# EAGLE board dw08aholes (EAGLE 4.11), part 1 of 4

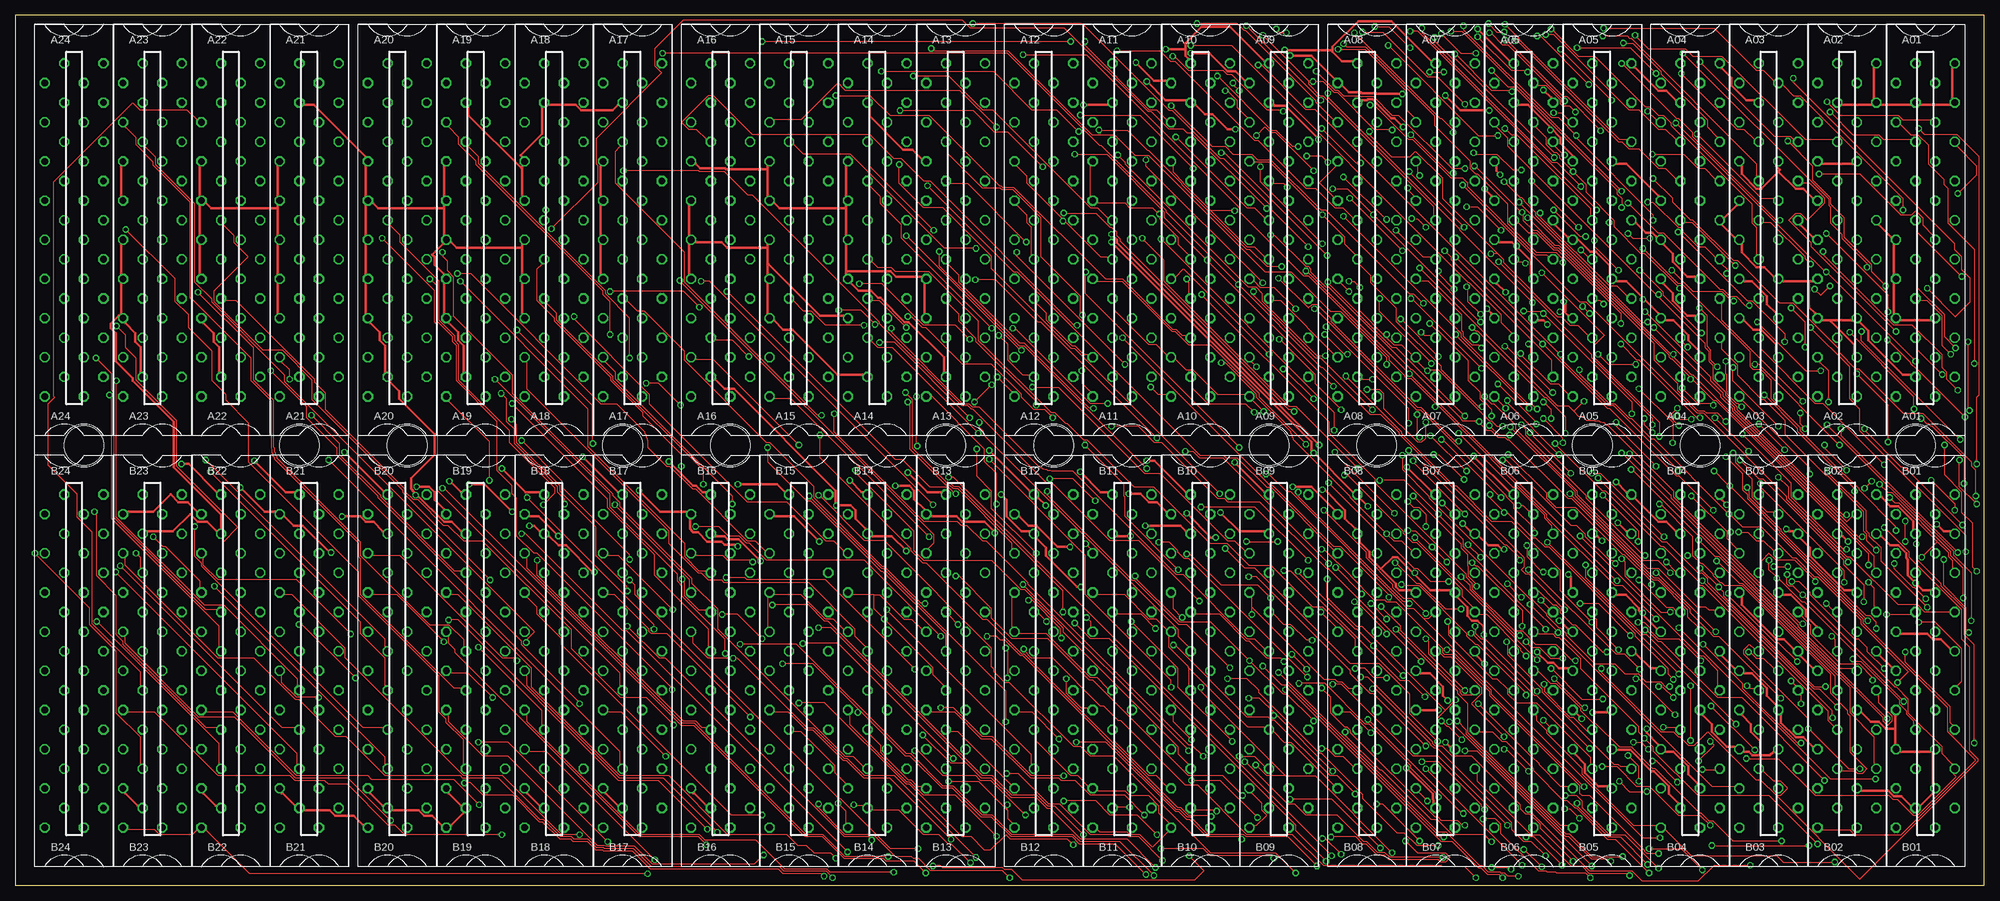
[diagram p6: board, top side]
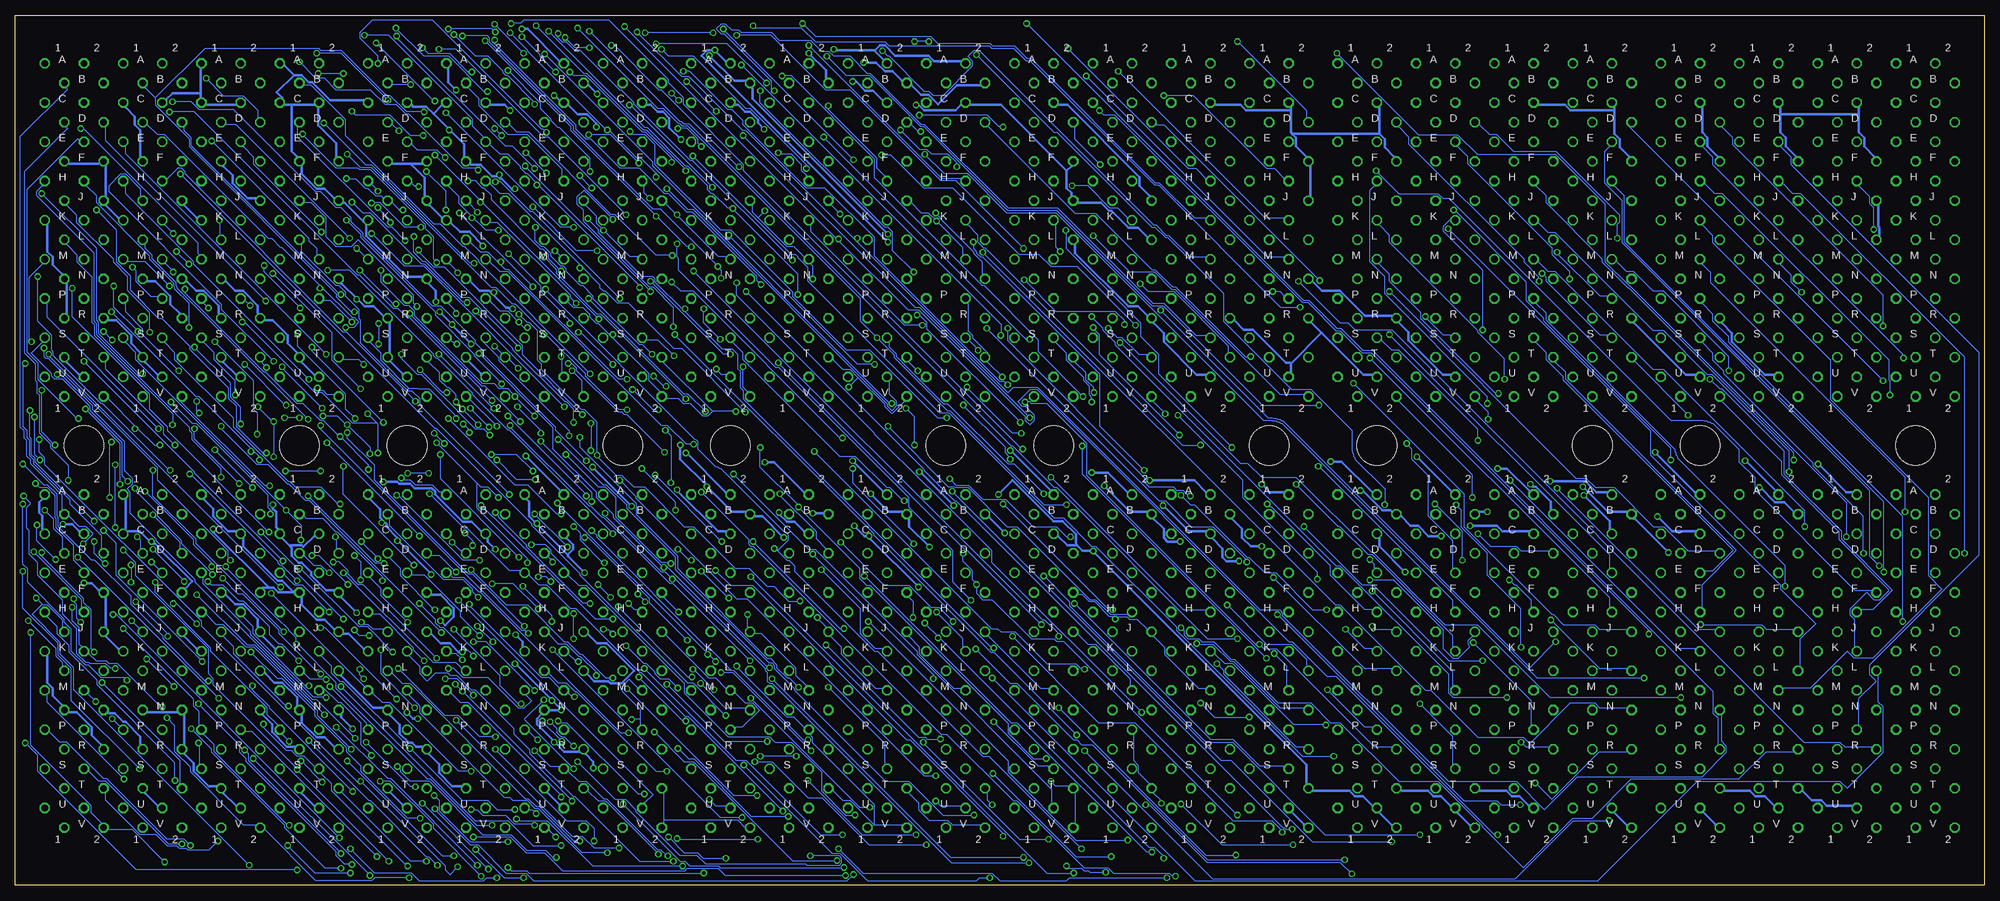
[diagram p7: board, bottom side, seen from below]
Size 319.07 x 140.96 mm. Coordinates in mm from the lower left corner, seen from the top.
Outline: 319.07,140.96 0,140.96 0,0 319.07,0 319.07,140.96
Copper layers (1*16): Top 0.035mm / dielectric 1.5mm / Bottom 0.035mm
Design rules "sierraproto": minimum track width 6mil, minimum drill 24mil, track to track 6mil, track to pad 6mil, pad to pad 10mil, via to via 6mil, smd to smd 6mil, copper to edge 25mil, drill to drill 10mil, minimum pad ring 10mil, minimum via ring 8mil, stop-mask expansion 0mil, vias tented up to drill 0mil, thermal gap 10mil
Net classes: 1 supply: width 0.381 mm

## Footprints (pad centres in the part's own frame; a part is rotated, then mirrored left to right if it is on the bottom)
H807 = drill 1.092 octagon: A1 4.763,28.575; A2 -1.587,28.575; B1 1.587,25.4; B2 -4.763,25.4; C1 4.763,22.225; C2 -1.587,22.225; D1 1.587,19.05; D2 -4.763,19.05; E1 4.763,15.875; E2 -1.587,15.875; F1 1.587,12.7; F2 -4.763,12.7; H1 4.763,9.525; H2 -1.587,9.525; J1 1.587,6.35; J2 -4.763,6.35; K1 4.763,3.175; K2 -1.587,3.175; L1 1.587,0; L2 -4.763,0; M1 4.763,-3.175; M2 -1.587,-3.175; N1 1.587,-6.35; N2 -4.763,-6.35; P1 4.763,-9.525; P2 -1.587,-9.525; R1 1.587,-12.7; R2 -4.763,-12.7; S1 4.763,-15.875; S2 -1.587,-15.875; T1 1.587,-19.05; T2 -4.763,-19.05; U1 4.763,-22.225; U2 -1.587,-22.225; V1 1.587,-25.4; V2 -4.763,-25.4
CBLOCK = hole 6.452: 7.938,68.263; 42.862,68.263

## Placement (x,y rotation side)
A01  M903  [H807]  309.55,104.61 0 top
A02  M903  [H807]  296.85,104.61 0 top
A03  M903  [H807]  284.15,104.61 0 top
A04  M903  [H807]  271.45,104.61 0 top
A05  M903  [H807]  257.16,104.61 0 top
A06  M907  [H807]  244.46,104.61 0 top
A07  M651  [H807]  231.76,104.61 0 top
A08  M651  [H807]  219.06,104.61 0 top
A09  M651  [H807]  204.77,104.61 0 top
A10  M651  [H807]  192.07,104.61 0 top
A11  M651  [H807]  179.37,104.61 0 top
A12  M651  [H807]  166.67,104.61 0 top
A13  W011  [H807]  152.39,104.61 0 top
A14  W011  [H807]  139.69,104.61 0 top
A15  W011  [H807]  126.98,104.61 0 top
A16  W011  [H807]  114.28,104.61 0 top
A17  W011  [H807]  100,104.61 0 top
A18  W011  [H807]  87.3,104.61 0 top
A19  W011  [H807]  74.6,104.61 0 top
A20  W011  [H807]  61.9,104.61 0 top
A21  W011  [H807]  47.61,104.61 0 top
A22  W011  [H807]  34.91,104.61 0 top
A23  W011  [H807]  22.21,104.61 0 top
A24  H807  [H807]  9.51,104.61 0 top
B01  M903  [H807]  309.55,34.76 0 top
B02  M903  [H807]  296.85,34.76 0 top
B03  M903  [H807]  284.15,34.76 0 top
B04  M903  [H807]  271.45,34.76 0 top
B05  M903  [H807]  257.16,34.76 0 top
B06  M101  [H807]  244.46,34.76 0 top
B07  M907  [H807]  231.76,34.76 0 top
B08  M651  [H807]  219.06,34.76 0 top
B09  M651  [H807]  204.77,34.76 0 top
B10  M651  [H807]  192.07,34.76 0 top
B11  M651  [H807]  179.37,34.76 0 top
B12  M651  [H807]  166.67,34.76 0 top
B13  M651  [H807]  152.39,34.76 0 top
B14  M651  [H807]  139.69,34.76 0 top
B15  M651  [H807]  126.98,34.76 0 top
B16  M517  [H807]  114.28,34.76 0 top
B17  M517  [H807]  100,34.76 0 top
B18  M517  [H807]  87.3,34.76 0 top
B19  M517  [H807]  74.6,34.76 0 top
B20  M517  [H807]  61.9,34.76 0 top
B21  M517  [H807]  47.61,34.76 0 top
B22  M517  [H807]  34.91,34.76 0 top
B23  M517  [H807]  22.21,34.76 0 top
B24  H807  [H807]  9.51,34.76 0 top
U$1  [CBLOCK]  3.16,3.01 0 top
U$2  [CBLOCK]  55.55,3.01 0 top
U$3  [CBLOCK]  107.94,3.01 0 top
U$4  [CBLOCK]  160.32,3.01 0 top
U$5  [CBLOCK]  212.71,3.01 0 top
U$6  [CBLOCK]  265.1,3.01 0 top

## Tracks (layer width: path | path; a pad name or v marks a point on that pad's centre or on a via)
-15V  (via drill 0.61)
  Top 0.381: v181.6,133.31 184.52,130.39 186.55,130.39 A10.B2 | v206.61,134.46 210.04,134.46 213.85,130.65 A08.B2 215,129.63 216.14,128.49 218.04,128.49 218.17,128.36 220.2,128.36 220.33,128.23 v224.78,128.23 | v190.49,134.84 193.53,134.84 196.45,131.92 197.72,131.92 199.25,130.39 A09.B2 | v65.01,64.6 67.04,64.6 67.93,63.72 67.93,62.45 69.45,60.92 B19.B2 | B23.B2 18.15,60.54 22.34,60.54 25.13,63.34 26.4,62.06 27.93,62.06 29.45,60.54 B22.B2 | v36.43,64.48 40.37,60.54 42.15,60.54 B21.B2 43.55,59.78 45.07,58.26 46.59,58.26 50.91,53.94 v51.17,53.94 | v88,56.6 84.82,59.78 83.3,59.78 B18.B2 | v101.08,63.97 104.51,60.54 108.82,60.54 B16.B2 109.33,59.4 109.33,57.75 109.84,57.24 110.6,57.24 112.13,55.72 114.41,55.72 114.92,55.21 116.83,55.21 v117.08,54.95 | v207,64.6 210.04,64.6 213.85,60.8 B08.B2 | v130.29,55.72 126.22,59.78 122.92,59.78 B15.B2 | v180.45,63.46 182.36,63.46 183.75,62.06 185.02,62.06 186.55,60.54 B10.B2 | v158.74,57.11 158.74,57.24 157.08,58.89 153.4,58.89 152.51,59.78 148.32,59.78 B13.B2 147.31,60.92 145.65,62.57 145.65,63.97 144.89,64.73 v142.61,64.73 | v170.93,54.83 168.9,54.83 165.47,58.26 164.2,58.26 162.67,59.78 B12.B2 | v194.55,56.35 193.79,56.35 v189.85,60.29 | v73.52,64.99 76.06,64.99 v80.5,60.54 | v177.66,105.5 178.55,104.61 178.55,104.1 v211.31,71.34
  Bottom 0.381: A12.B2 162.67,129.63 166.48,129.63 169.53,126.58 171.05,128.11 172.32,128.11 173.85,129.63 A11.B2 175.37,130.39 176.9,131.92 178.17,131.92 179.56,133.31 v181.6,133.31 | v206.61,134.46 202.55,130.39 200.77,130.39 A09.B2 199.63,129.25 199.63,127.47 v177.66,105.5 | v224.78,128.23 226.17,129.63 226.3,129.63 A07.B2 | v190.49,134.84 187.69,132.04 187.69,130.77 A10.B2 | v65.01,64.6 60.95,60.54 57.9,60.54 B20.B2 56.75,59.4 56.63,59.4 v51.17,53.94 | v36.43,64.48 36.31,64.48 33.89,62.06 32.37,62.06 30.85,60.54 B22.B2 | v88,56.6 90.03,56.6 91.68,58.26 92.95,58.26 94.47,59.78 B17.B2 96,60.54 96.25,60.8 97.52,60.8 100.7,63.97 v101.08,63.97 | v130.29,55.72 132.32,55.72 132.95,56.35 132.95,57.75 134.61,59.4 B14.B2 135.62,60.54 138.42,60.54 v142.61,64.73 | v180.45,63.46 177.53,60.54 175.37,60.54 B11.B2 174.23,59.4 174.23,58.13 v170.93,54.83 | v158.74,57.11 161.28,59.65 B12.B2 | v194.55,56.35 197.98,59.78 199.25,59.78 B09.B2 200.77,60.54 202.93,60.54 v207,64.6 207.25,64.99 211.31,69.05 v211.31,71.34 | v189.85,60.29 188.07,60.29 B10.B2 | v117.08,54.95 118.86,54.95 120.25,56.35 120.25,57.75 121.91,59.4 B15.B2 | v73.52,64.99 73.14,64.6 72.63,64.6 70.22,62.19 70.22,60.92 B19.B2 | v80.5,60.54 81.77,60.54 B18.B2
A06U1  (via drill 0.61)
  Top 0.152: 169.91,107.78 163.94,113.75 163.94,114.9 162.29,116.55 A12.F2 | 169.91,107.78 175.88,101.82 177.02,101.82 A11.M2 | A12.M2 164.7,102.2 164.7,106.64 163.94,107.4 163.94,108.55 162.29,110.2 A12.J2 | A11.F2 174.23,116.55 174.23,111.72 A11.J2 175.37,110.58 179.82,110.58 180.58,109.82 184.26,109.82 185.02,109.05 v185.41,108.8 185.41,108.04 188.45,104.99 188.45,103.85 190.1,102.2 A10.M2 | v189.85,98.26 190.1,98.01 190.1,95.85 A10.P2 | v169.78,107.66 169.91,107.78 | 193.79,109.31 199.63,103.47 200.77,103.47 202.42,101.82 A09.M2 | 193.79,109.31 189.34,113.75 189.34,113.88 187.69,115.53 187.69,116.55 A10.F2 | A08.F2 213.98,116.55 211.31,113.88 213.73,111.47 A08.J2 | v233.92,73.24 242.68,64.48 243.32,64.48 247.76,60.03 247.76,59.52 248.91,58.38 248.91,57.75 B06.C1 | v237.73,77.56 237.09,77.56 231,83.65 231,84.16 223.76,91.4 223.76,93.56 219.57,97.75 219.57,98.89 217.79,100.67 A08.M2 217.16,102.2 215.38,103.97 215.38,105.12 v211.82,108.67 203.31,117.18 200.77,117.18 A09.F2 | v227.57,115.02 227.32,115.28 227.32,116.55 A07.F2 | v225.66,112.99 225.66,112.74 226.68,111.72 A07.J2 | v223.76,106.13 228.08,101.82 229.47,101.82 A07.M2 | v231.63,102.83 232.65,101.82 232.65,101.43 248.91,85.18 248.91,83.15 A06.U1 | v197.6,109.31 193.79,109.31
  Bottom 0.152: v189.85,98.26 189.85,100.42 190.1,100.67 A10.M2 191.25,101.82 192.9,103.47 194.04,103.47 198.74,108.17 | v185.41,108.8 186.8,110.2 186.93,110.2 A10.J2 | 198.74,108.17 199.63,109.05 199.63,110.2 A09.J2 | A12.M2 165.47,102.2 165.47,103.34 v169.78,107.66 171.05,108.93 172.2,108.93 173.85,110.58 A11.J2 | 211.82,108.55 213.73,110.45 A08.J2 | 211.82,108.55 205.09,101.82 203.95,101.82 A09.M2 | A08.M2 218.17,101.82 219.44,101.82 v223.76,106.13 224.9,107.28 224.9,108.42 226.68,110.2 A07.J2 | v233.92,73.24 233.92,73.75 v237.73,77.56 | v227.57,115.02 227.57,114.9 v225.66,112.99 | v231.63,102.83 230.74,101.94 A07.M2 | 211.82,108.55 v211.82,108.67 | 198.74,108.17 v197.6,109.31
A06V1  (via drill 0.61)
  Top 0.152: v159.12,82.38 161.53,79.97 A12.V2 | A11.T2 173.85,85.94 173.21,85.94 171.82,87.34 171.31,87.34 167.12,91.53 167.12,92.67 165.47,94.32 A12.P2 | v184.01,80.73 185.15,79.59 186.55,79.59 A10.V2 | A11.P2 178.17,94.32 178.17,93.18 183.75,87.59 184.9,87.59 186.55,85.94 A10.T2 188.07,85.18 189.72,83.53 190.87,83.53 194.8,79.59 199.25,79.59 A09.V2 200.52,78.57 v202.3,76.8 | v201.15,84.04 200.39,84.8 A09.T2 | v172.83,83.4 172.83,81.37 174.23,79.97 A11.V2 | A09.P2 203.95,94.7 205.09,94.7 213.73,86.07 A08.T2 | 221.98,88.99 223.38,87.59 224.65,87.59 226.3,85.94 A07.T2 227.32,84.8 228.71,83.4 v228.84,83.4 229.22,83.53 230.62,83.53 238.87,75.27 239.25,75.27 240.14,74.38 v241.03,74.38 | 221.98,88.99 217.79,93.18 217.79,94.32 A08.P2 | v222.24,89.24 221.98,88.99
  Bottom 0.152: v159.12,82.38 161.53,84.8 A12.T2 161.53,86.32 163.94,88.73 163.94,89.12 164.7,89.88 164.7,94.32 A12.P2 | 182.48,82.26 183.75,83.53 184.9,83.53 186.55,85.18 A10.T2 | 182.48,82.26 178.17,77.94 178.17,77.56 177.02,76.42 174.99,78.45 A11.V2 | 182.48,82.26 v184.01,80.73 | v201.15,84.04 201.15,80.73 200.39,79.97 A09.V2 | v172.83,83.4 174.23,84.8 A11.T2 | 206.11,76.8 206.87,76.03 207.63,76.03 209.66,78.07 210.81,78.07 211.57,78.83 213.6,78.83 A08.V2 214.62,79.97 216.39,81.75 216.39,82.89 222.49,88.99 | 206.11,76.8 214.11,84.8 A08.T2 | 222.49,88.99 224.52,91.02 224.9,91.02 225.92,92.04 225.92,92.42 227.06,93.56 228.59,93.56 229.6,94.58 A07.P2 | v228.84,83.4 227.32,81.88 227.32,79.97 A07.V2 | v241.03,74.38 245.35,78.7 245.48,78.7 A06.V1 | 222.49,88.99 v222.24,89.24 | v202.3,76.8 206.11,76.8
B07U1  (via drill 0.61)
  Top 0.152: B09.V2 200.77,9.74 201.15,9.74 202.8,11.39 202.04,12.15 202.04,13.3 200.39,14.95 B09.T2 | v211.57,44.29 213.98,41.87 B08.J2 | B08.T2 213.73,16.22 206.74,23.2 205.6,23.2 203.95,24.85 B09.P2 202.42,25.62 199.76,25.62 190.1,35.27 | B15.J2 121.91,41.87 121.91,46.7 B15.F2 122.92,47.08 127.37,47.08 131.3,43.14 132.57,43.14 134.22,41.49 B14.J2 | v234.68,11.65 234.43,11.65 v219.19,26.89 | 139.18,47.08 140.07,47.08 144,43.14 145.27,43.14 146.92,41.49 B13.J2 | 139.18,47.08 135.62,47.08 B14.F2 | B12.F2 161.53,46.7 161.53,41.87 B12.J2 162.67,40.73 167.12,40.73 174.23,33.62 175.37,33.62 177.02,31.97 B11.M2 | 190.1,35.27 190.1,35.4 186.93,38.57 186.93,40.35 B10.J2 186.55,41.49 184.9,43.14 183.75,43.14 179.82,47.08 175.37,47.08 B11.F2 | 190.1,35.27 190.1,32.35 B10.M2 | v189.09,43.4 187.69,44.79 187.69,46.7 B10.F2 | v200.39,43.9 200.39,45.05 | 200.39,45.05 200.39,46.7 B09.F2 | v173.59,43.4 174.23,42.76 174.23,41.87 B11.J2 | 139.18,47.08 139.18,44.79 v140.83,43.14 148.7,35.27 148.7,34.12 150.48,32.35 B13.M2 | 200.39,45.05 212.08,33.36 213.85,33.36 214.23,32.98 215,32.98 216.01,31.97 216.77,31.97 B08.M2
  Bottom 0.152: 213.98,10.63 213.98,14.95 B08.T2 | 213.98,10.63 213.98,10.12 B08.V2 | 213.98,10.63 202.04,10.63 200.77,9.36 B09.V2 | B09.P2 202.42,25.62 201.28,25.62 198.49,28.41 199.63,29.55 200.77,29.55 202.42,31.2 B09.M2 203.95,31.97 205.6,33.62 206.74,33.62 213.73,40.6 B08.J2 | v211.57,44.29 213.98,46.7 B08.F2 | B15.M2 126.1,31.97 127.37,31.97 132.83,37.43 132.83,38.57 134.61,40.35 B14.J2 135.62,41.49 137.27,43.14 138.54,43.14 138.92,43.52 140.83,43.52 | 140.83,43.52 141.72,43.52 144.13,45.94 145.02,45.94 146.16,47.08 146.92,47.08 B13.F2 | 217.79,26.89 217.79,28.54 220.71,31.46 220.71,32.22 219.57,33.36 218.17,31.97 B08.M2 | 217.79,26.89 217.79,26 B08.P2 | v234.68,11.65 235.19,12.15 235.82,12.15 B07.U1 | 217.79,26.89 v219.19,26.89 | B14.M2 138.42,32.35 138.42,33.49 144,39.08 145.27,39.08 146.92,40.73 B13.J2 | B13.M2 151.5,31.97 152.89,31.97 161.4,40.48 B12.J2 | B12.M2 165.85,31.97 166.99,31.97 172.58,37.55 172.58,38.7 174.23,40.35 B11.J2 | B11.M2 178.55,31.97 179.69,31.97 185.28,37.55 185.28,38.7 186.93,40.35 B10.J2 187.69,41.87 189.09,43.27 v189.09,43.4 | B10.M2 190.87,32.35 192.52,34 192.52,35.14 198.11,40.73 199.25,40.73 B09.J2 200.39,41.87 v200.39,43.9 | v173.59,43.4 173.59,46.06 174.23,46.7 B11.F2 | v140.83,43.14 140.83,43.52
B07V1  (via drill 0.61)
  Top 0.152: v133.34,13.3 134.61,12.03 134.61,10.12 B14.V2 | B15.P2 126.1,24.85 127.37,24.85 132.83,19.39 132.83,18.25 134.61,16.47 B14.T2 | B13.T2 146.92,16.09 146.16,16.09 145.15,17.11 144.64,17.11 140.19,21.55 140.19,22.7 138.42,24.47 B14.P2 | B13.P2 151.5,24.85 152.77,24.85 B12.T2 | B12.P2 165.47,24.47 165.47,23.33 171.05,17.74 172.2,17.74 173.85,16.09 B11.T2 175.37,15.33 179.82,15.33 180.58,14.57 183.63,14.57 185.28,12.92 185.28,11.77 186.93,10.12 B10.V2 186.8,8.73 184.26,6.18 182.23,8.22 180.58,8.22 180.2,8.6 175.75,8.6 175.37,8.98 B11.V2 | 160.77,12.15 160.77,10.88 161.53,10.12 B12.V2 | 160.77,12.15 v160.77,13.04 | v151.24,16.85 156.07,16.85 160.77,12.15 | B11.P2 178.17,24.47 178.17,23.33 183.75,17.74 184.9,17.74 186.55,16.09 B10.T2 | v231.51,7.84 230.87,7.84 206.23,32.47 205.22,32.47 v202.17,35.52
  Bottom 0.152: B13.V2 147.31,10.12 147.31,14.95 B13.T2 148.32,16.09 150.48,16.09 v151.24,16.85 | v133.34,13.3 133.34,13.68 134.61,14.95 B14.T2 135.24,16.47 137.02,18.25 137.02,19.39 137.78,20.16 137.78,24.47 B14.P2 | B12.V2 162.67,9.74 167.12,9.74 167.88,10.5 170.93,10.5 172.58,12.15 172.58,13.3 174.23,14.95 B11.T2 | v160.77,13.04 161.53,13.81 161.53,14.95 B12.T2 | 179.82,9.74 175.37,9.74 B11.V2 | 179.82,9.74 183.75,13.68 184.9,13.68 186.55,15.33 B10.T2 | 179.82,9.74 179.82,13.04 189.85,23.08 189.85,23.96 190.1,24.22 190.1,24.47 B10.P2 191.25,25.62 192.9,27.27 194.04,27.27 202.17,35.4 v202.17,35.52 | v231.51,7.84 232.65,8.98 B07.V1
GND  (via drill 0.61)
  Top 0.381: A22.U2 33.01,83.15 33.01,87.21 32.12,88.1 32.12,89.5 30.46,91.15 A22.R2 | A21.R2 42.53,92.67 42.53,97.5 A21.N2 42.53,99.02 42.53,103.85 A21.L2 42.53,105.37 42.53,109.69 | 42.53,109.69 42.53,110.2 A21.J2 42.53,111.72 42.53,116.55 A21.F2 | A22.N2 29.83,99.02 29.83,103.85 A22.L2 29.83,105.37 29.83,110.2 A22.J2 | A22.F2 29.83,116.55 29.83,111.72 A22.J2 | A23.J2 17.13,111.72 17.13,116.55 A23.F2 | B23.C2 21.32,57.37 25.51,57.37 28.31,60.16 29.58,58.89 31.1,58.89 32.62,57.37 B22.C2 33.39,57.75 33.39,60.03 25.64,67.78 25.64,75.15 19.04,81.75 19.04,82.13 16.24,84.92 16.24,89.5 15.48,90.26 15.48,91.02 16.75,92.29 A23.R2 | A23.U2 20.3,83.15 20.3,87.21 19.42,88.1 19.42,89.5 17.77,91.15 A23.R2 | A23.R2 17.13,92.67 17.13,97.5 A23.N2 17.13,99.02 17.13,103.85 A23.L2 | 42.53,109.69 31.73,109.69 30.85,110.58 A22.J2 | v52.94,59.78 55.87,59.78 56.75,58.89 58.02,58.89 59.55,57.37 B20.C2 | v83.3,58.26 84.06,58.26 84.95,57.37 B18.C2 86.47,56.6 88,55.08 89.27,55.08 93.58,50.76 v93.84,50.76 | B19.C2 72.25,57.37 70.72,58.89 69.45,58.89 65.14,63.21 v64.88,63.21 64.63,63.59 64.63,63.72 64.12,64.22 64.12,66 67.93,69.81 67.93,73.11 62.21,78.83 62.21,80.1 60.69,81.62 A20.U2 59.93,83.15 59.93,87.46 59.04,88.35 59.04,89.62 57.52,91.15 A20.R2 56.75,92.67 56.75,97.5 A20.N2 56.75,99.02 56.75,103.85 A20.L2 56.75,105.37 56.75,110.2 A20.J2 | A18.R2 82.15,92.67 82.15,97.5 A18.N2 82.15,99.02 82.15,103.34 | 82.15,103.34 82.15,103.85 A18.L2 | 69.45,109.69 69.45,110.2 A19.J2 69.45,111.72 69.45,116.55 A19.F2 | 69.45,109.69 69.45,105.37 A19.L2 | A19.U2 72.63,83.15 72.63,87.46 71.74,88.35 71.74,89.62 70.22,91.15 A19.R2 69.45,92.67 69.45,97.5 A19.N2 69.45,99.02 67.93,100.55 67.93,101.82 67.55,102.2 69.33,103.97 A19.L2
  Top 0.381: 82.15,103.34 71.49,103.34 70.6,104.23 A19.L2 | 82.15,116.17 82.15,116.55 A18.F2 82.15,118.07 81.9,118.33 85.33,121.75 85.33,126.07 A18.C2 86.47,126.45 90.79,126.45 91.68,125.56 96.76,125.56 97.65,126.45 A17.C2 | 82.15,116.17 82.15,111.72 A18.J2 | A19.C2 73.39,126.07 73.39,124.8 82.03,116.17 82.15,116.17 | A20.J2 56.75,111.72 56.75,116.55 A20.F2 56.75,118.07 48.37,126.45 46.72,126.45 A21.C2 | 69.45,109.69 58.79,109.69 57.9,110.58 A20.J2 | A04.R1 272.27,92.29 271,92.29 268.59,94.7 268.59,95.97 267.07,97.5 A04.N2 | A04.T1 273.16,86.32 271.13,88.35 271.13,89.12 268.72,91.53 267.45,91.53 A04.R2 266.3,92.67 263.89,95.08 | 263.89,95.08 261.1,97.88 259.45,97.88 A05.N1 258.43,99.02 258.43,100.42 256.14,102.7 255.26,102.7 253.1,104.86 A05.L2 251.7,104.99 251.57,104.99 249.54,107.02 A06.K1 | A03.T1 285.35,86.32 285.35,87.59 282.94,90 281.67,90 280.15,91.53 A03.R2 | 263.89,95.08 v263.76,94.96 | A02.K1 301.99,107.02 304.02,104.99 A01.L2 304.4,103.85 304.4,99.02 A01.N2 304.4,97.5 304.4,92.67 A01.R2 305.55,91.53 310.37,91.53 A01.R1 | A03.J2 279,110.2 276.97,108.17 A04.K1 276.59,107.02 278.62,104.99 A03.L2 279.77,103.85 279.77,102.58 282.18,100.16 283.45,100.16 284.97,98.64 A03.N1 286.5,97.88 290.69,97.88 | 285.74,115.66 285.99,115.91 285.35,116.55 A03.F1 | 285.74,115.66 282.94,112.86 282.18,112.86 279.77,115.28 279.77,116.55 A03.F2 | A03.K1 289.29,107.02 291.32,104.99 A02.L2 | 285.74,115.66 288.53,112.86 289.8,112.86 291.32,111.34 A02.J2 | A03.N2 280.15,97.88 281.42,97.88 283.83,95.47 283.83,94.2 285.35,92.67 A03.R1 | 290.69,97.88 291.32,97.88 A02.N2
  Top 0.381: 294.24,91.53 297.67,91.53 A02.R1 298.94,91.27 300.34,89.88 300.34,88.35 305.93,82.77 307.2,82.77 A01.U2 | 294.24,91.53 292.85,91.53 A02.R2 291.7,92.67 290.69,93.69 290.69,97.88 | A02.T1 298.05,86.32 298.05,87.59 294.24,91.4 294.24,91.53 | v238.11,112.86 239.25,111.72 239.25,111.59 A06.J2 | v240.65,115.15 240.02,115.79 240.02,116.55 A06.F2 | v247.64,128.87 248.91,127.6 A06.C1 | v238.49,93.43 239.25,92.67 239.25,92.54 A06.R2 | v241.54,96.1 240.14,97.5 240.02,97.5 A06.N2 | 243.25,103.53 245.6,101.18 245.6,99.15 245.73,99.02 A06.N1 | 243.25,103.53 242.56,104.23 240.4,104.23 A06.L2 | 248.91,122.64 250.43,121.12 250.43,120.23 252.59,118.07 A05.F2 | 248.91,122.64 245.1,126.45 243.57,126.45 A06.C2 | v243.32,103.59 243.25,103.53 | v248.78,122.39 248.78,122.52 248.91,122.64 | A02.F2 292.85,116.93 297.67,116.93 A02.F1 | A02.C2 296.02,126.45 300.85,126.45 A02.C1 | A02.A1 301.23,132.42 301.23,127.6 A02.C1 | A02.C1 302.37,126.45 307.2,126.45 A01.C2 308.72,126.45 313.55,126.45 A01.C1 313.93,127.6 313.93,132.42 A01.A1 | A05.A1 262.37,132.55 262.49,132.55 266.3,128.74 267.57,128.74 269.1,127.22 A04.C2 | v248.27,90.89 247.64,91.53 246.75,91.53 A06.R1 | 251.06,92.93 v250.3,92.93 | 251.06,92.93 251.7,92.29 A05.R2 | v245.22,87.72 245.73,87.21 245.73,86.32 A06.T1 | A05.K1 262.62,107.4 264.27,105.75 265.29,105.75 265.92,105.12 265.92,104.99 A04.L2 267.07,103.85 268.59,102.32 268.59,101.05 271,98.64 272.27,98.64 A04.N1 | v250.94,94.58 251.19,94.32 251.19,93.05 251.06,92.93 | A03.C2 281.8,127.22 280.53,127.22 278.12,129.63 278.12,130.9 276.59,132.42 A04.A1 | A05.F1 259.45,116.93 261.1,116.93 266.3,111.72 A04.J2
  Top 0.381: v224.9,122.9 223.51,124.29 223,124.29 219.95,127.34 219.19,127.34 219.06,127.22 218.17,127.22 A08.C2 | A14.C2 138.42,126.07 138.42,124.68 143.88,119.21 145.4,119.21 146.92,117.69 A13.F2 | v173.09,126.45 177.02,126.45 A11.C2 | v183.37,130.26 186.42,127.22 189.72,127.22 A10.C2 191.25,126.45 192.77,124.93 194.04,124.93 196.45,122.52 v197.72,122.52 | v211.19,120.87 211.19,120.99 205.85,126.33 204.07,126.33 203.95,126.45 A09.C2 | A13.R2 147.31,92.67 147.31,97.5 A13.N2 146.92,98.64 142.73,98.64 141.84,99.53 134.61,99.53 | 134.61,99.53 134.61,103.85 A14.L2 134.61,105.37 134.61,109.69 | 134.61,99.53 134.61,99.02 A14.N2 135.37,97.62 136.64,96.35 138.67,96.35 139.81,95.21 140.19,95.21 144.13,91.27 144.77,91.27 150.48,85.56 150.48,83.15 A13.U2 | 134.61,109.69 134.61,110.2 A14.J2 134.61,111.72 134.61,116.55 A14.F2 | A17.N2 94.85,99.02 94.85,103.85 A17.L2 94.85,105.37 94.85,110.2 A17.J2 94.85,111.72 94.85,116.55 A17.F2 | 121.91,116.04 121.91,116.55 A15.F2 | 121.91,116.04 121.91,111.72 A15.J2 122.92,110.58 123.81,109.69 134.61,109.69 | A16.N2 109.2,99.02 109.2,103.85 A16.L2 | A16.J2 109.2,110.2 109.2,105.37 A16.L2 | 121.91,116.04 115.17,116.04 115.05,116.17 110.98,116.17 110.22,116.93 A16.F2 | v238.87,125.56 234.17,125.56 v231.76,127.98 | v246.62,37.81 248.4,36.03 249.29,36.03 250.18,35.14 251.7,35.14 B05.L2 | v250.18,42.89 250.3,42.89 251.7,41.49 B05.J2 | v257.16,55.84 256.4,56.6 256.27,56.6 B05.C2 | v259.7,58.76 261.1,57.37 261.22,57.37 B05.C1 | v277.35,61.68 276.59,62.45 276.59,62.57 B04.A1 | B04.C2 269.1,57.37 267.57,58.89 266.3,58.89 262.49,62.7 262.37,62.7 B05.A1 261.22,63.72 261.1,63.72 v259.45,65.37
  Top 0.381: v251.7,50.38 252.08,50 252.08,48.22 B05.F2 | B05.T1 258.05,16.09 256.53,16.09 254.37,18.25 254.37,19.65 252.72,21.3 B05.R2 | B02.F1 297.67,47.84 296.4,47.84 290.81,53.43 290.81,54.7 289.29,56.22 B03.C1 288.15,57.37 287.39,57.37 v287,57.75 | v253.86,27.01 252.97,27.9 B05.N2 | v255.64,28.03 258.05,28.03 B05.N1 | B04.L2 265.92,35.14 265.03,35.14 262.62,37.55 B05.K1 | 263.64,44.03 266.05,41.62 B04.J2 | 263.64,44.03 263.13,44.54 263.13,44.92 260.97,47.08 259.45,47.08 B05.F1 | v263.76,44.16 263.64,44.03 | v297.04,55.72 296.15,56.6 296.02,56.6 B02.C2 | B01.F1 310.37,47.84 309.1,47.84 v307.96,48.98 306.69,50.25 306.69,52.79 306.44,53.05 306.44,53.81 305.17,55.08 303.9,55.08 302.37,56.6 B02.C1 | B01.C2 307.58,57.75 307.58,59.02 305.17,61.43 303.9,61.43 302.37,62.95 B02.A1 | v311.39,58.51 312.53,57.37 313.55,57.37 B01.C1 | B02.T1 299.2,15.33 303.51,15.33 304.4,14.44 305.67,14.44 307.2,12.92 B01.U2 308.72,12.92 310.75,14.95 B01.T1 310.75,16.47 310.75,21.3 B01.R1 310.37,21.68 305.55,21.68 B01.R2 304.66,22.82 304.66,25.36 | B01.L2 304.15,35.27 302.12,37.3 B02.K1 | 304.66,25.36 304.66,27.65 B01.N2 | B01.J2 305.55,40.73 309.87,40.73 310.75,39.84 312.02,39.84 313.55,38.32 B01.K1 | 282.81,21.04 284.34,21.04 284.97,21.68 B03.R1 | 282.81,21.04 281.54,21.04 280.91,21.68 280.15,21.68 B03.R2 278.62,22.44 277.35,22.44 274.94,24.85 274.94,26.12 273.42,27.65 B04.N1 | 282.81,21.04 282.81,23.33 281.29,24.85 281.29,26.12 279.77,27.65 B03.N2 | B05.R1 259.45,21.93 261.73,21.93 265.16,18.5 265.54,18.5 267.96,16.09 267.96,14.82 269.48,13.3 B04.U2 | B04.T1 272.65,16.47 271.13,18 271.13,19.27 268.72,21.68 267.45,21.68 B04.R2 266.3,22.82 264.4,24.73 v264.4,25.36
  Top 0.381: B04.K1 276.59,37.17 278.62,35.14 B03.L2 280.15,34.38 281.42,34.38 283.83,31.97 283.83,30.7 285.35,29.17 B03.N1 286.12,27.65 286.12,26.38 288.53,23.96 289.8,23.96 291.32,22.44 B02.R2 | B02.L2 291.32,35.14 289.29,37.17 B03.K1 288.15,38.32 286.62,39.84 285.35,39.84 279.77,45.43 279.77,46.7 B03.F2 | B03.F1 286.5,47.08 287.77,47.08 290.18,44.67 290.18,43.65 291.96,41.87 B02.J2 | 304.66,25.36 303.13,25.36 301.99,26.51 300.72,26.51 299.2,28.03 B02.N1 | v231.76,23.2 232.52,22.44 232.65,22.44 B07.R1 | B07.N2 v230.62,28.41 | v238.11,35.9 236.84,37.17 B07.K1 | v225.41,19.01 225.54,19.01 229.73,14.82 229.73,13.93 229.86,13.81 229.86,13.3 B07.U2 | v232.14,29.93 231.38,30.7 231.38,32.22 229.22,34.38 227.7,34.38 B07.L2 | v180.71,56.6 178.55,56.6 B11.C2 | v183.12,58.26 188.83,58.26 189.72,57.37 B10.C2 | v195.31,60.41 198.36,57.37 202.42,57.37 B09.C2 | v234.55,58.64 235.82,57.37 B07.C1 237.22,56.6 238.75,55.08 240.27,55.08 240.9,54.45 v241.29,54.45 | 221.35,51.27 223.76,48.86 223.76,48.35 224.27,47.84 226.3,47.84 B07.F2 | 221.35,51.27 219.44,53.18 219.44,54.06 217.79,55.72 217.79,56.22 B08.C2 217.16,57.75 215.5,59.4 215.5,60.8 212.2,64.1 v211.82,64.1 | 226.68,50.51 224.01,53.18 223.25,53.18 221.35,51.27 | 226.68,50.51 229.35,47.84 232.65,47.84 B07.F1 233.67,46.7 235.32,45.05 235.32,43.65 236.08,42.89 236.97,42.89 237.98,41.87 v237.98,40.6 | 226.68,50.51 v226.81,50.63 | B21.T2 43.16,14.95 43.29,14.95 45.32,12.92 B21.U2 46.72,12.15 50.91,12.15 51.8,11.27 54.85,11.27 56.37,9.74 B20.V2 | B23.U2 19.92,12.92 19.8,12.92 17.77,14.95 B23.T2 | B22.U2 32.62,12.92 32.5,12.92 30.46,14.95 B22.T2
  Top 0.381: B16.T2 109.84,14.95 109.97,14.95 112,12.92 B16.U2 | B17.T2 95.62,14.95 97.65,12.92 B17.U2 | B18.T2 82.92,14.95 84.95,12.92 B18.U2 | B20.T2 57.52,14.95 59.55,12.92 B20.U2 61.07,12.15 65.39,12.15 66.28,11.27 67.55,11.27 69.07,9.74 B19.V2 70.6,9.74 72.63,11.77 B19.U2 72.25,12.92 70.22,14.95 B19.T2 | v120.76,52.54 117.21,56.1 115.43,56.1 114.92,56.6 113.4,56.6 B16.C2 | v144.38,54.19 141.97,56.6 138.8,56.6 B14.C2 137.78,57.75 136.13,59.4 136.13,60.8 135.37,61.56 v133.08,61.56 132.95,61.94 132.95,63.97 116.44,80.48 114.92,80.48 113.4,82 A16.U2 | v159.75,63.34 160.64,62.45 160.64,59.78 163.05,57.37 164.32,57.37 B12.C2 165.47,56.22 166.99,54.7 166.99,53.43 172.07,48.35 v172.71,48.35 | A14.U2 137.4,82.77 133.21,82.77 125.97,90 124.44,90 122.92,91.53 A15.R2 121.91,92.67 121.91,97.5 A15.N2 121.91,99.02 121.91,100.67 | 121.91,100.67 121.91,103.34 | 121.91,103.34 121.91,103.85 A15.L2 | A14.R2 134.22,92.29 130.41,92.29 122.03,100.67 121.91,100.67 | A16.L2 110.22,104.23 114.41,104.23 115.3,103.34 121.91,103.34
  Bottom 0.381: A21.C2 45.7,126.07 45.7,122.01 44.82,121.12 44.82,119.72 43.16,118.07 A21.F2 | A22.U2 34.02,82.77 35.55,82.77 40.88,88.1 40.88,89.5 42.53,91.15 A21.R2 | 33.01,124.93 33.01,122.01 32.12,121.12 32.12,119.72 30.46,118.07 A22.F2 | 33.01,124.93 33.01,126.07 A22.C2 | 20.3,124.93 20.3,122.01 19.42,121.12 19.42,119.72 17.77,118.07 A23.F2 | 20.3,124.93 20.3,126.07 A23.C2 | A23.J2 17.13,110.2 17.13,106.77 17,106.64 17,105.24 A23.L2 | 33.01,124.93 20.3,124.93 | v52.94,59.78 50.53,57.37 46.72,57.37 B21.C2 | v83.3,58.26 78.98,58.26 78.09,57.37 73.77,57.37 B19.C2 | v93.84,50.76 98.03,54.95 98.03,56.22 B17.C2 | v64.88,63.21 60.69,59.02 60.69,57.75 B20.C2 | A21.U2 46.72,82.77 48.37,82.77 56.75,91.15 A20.R2 | 59.93,125.56 59.93,121.75 59.04,120.87 59.04,119.6 57.52,118.07 A20.F2 | 59.93,125.56 59.93,126.07 A20.C2 | A19.C2 72.25,126.45 67.93,126.45 67.04,125.56 59.93,125.56 | A05.U2 256.27,82.77 256.27,82.89 258.3,84.92 A05.T1 258.43,86.32 258.43,91.15 A05.R1 259.45,92.29 260.97,93.81 262.49,93.81 263.7,95.02 | 263.7,95.02 266.18,97.5 266.3,97.5 A04.N2 | A03.U2 283.32,82.77 285.35,84.8 A03.T1 | A04.U2 270.62,82.77 272.65,84.8 A04.T1 273.42,86.32 274.94,87.85 274.94,89.12 277.35,91.53 278.62,91.53 A03.R2 279.77,92.67 279.77,93.94 282.18,96.35 283.45,96.35 284.97,97.88 A03.N1 | v263.76,94.96 263.7,95.02 | A02.K1 302.37,108.17 304.4,110.2 A01.J2 304.4,111.72 304.4,116.55 A01.F2 305.55,116.93 310.37,116.93 A01.F1 | A01.R1 310.75,92.67 310.75,97.5 A01.N1 311.52,99.02 313.04,100.55 313.04,101.82 313.93,102.7 313.93,107.02 A01.K1 | A02.J2 291.7,110.2 289.67,108.17 A03.K1
  Bottom 0.381: A03.J2 280.15,111.34 281.42,111.34 283.83,113.75 283.83,115.02 285.35,116.55 A03.F1 | A01.U2 308.72,82.77 310.75,84.8 A01.T1 | A02.U2 296.02,82.77 298.05,84.8 A02.T1 298.82,86.32 300.34,87.85 300.34,89.12 302.75,91.53 304.02,91.53 A01.R2 | A02.N1 297.67,97.88 296.4,97.88 293.99,95.47 293.99,94.2 292.47,92.67 A02.R2 | A03.R1 286.12,92.67 286.12,93.94 288.53,96.35 289.8,96.35 291.32,97.88 A02.N2 | v238.11,112.86 238.62,112.86 240.27,114.52 240.52,114.52 240.9,114.9 | 240.9,114.9 241.79,114.9 243.7,116.8 245.22,116.8 245.35,116.93 A06.F1 246.37,118.07 246.37,120.1 248.72,122.45 | 240.9,114.9 v240.65,115.15 | 251.32,125.06 249.92,126.45 A06.C1 | 251.32,125.06 252.46,126.2 254.62,126.2 254.87,126.45 A05.C2 | v247.64,128.87 248.91,130.14 248.91,132.42 A06.A1 | 248.72,122.45 251.32,125.06 | v238.49,93.43 239,93.43 239.13,93.56 239.51,93.56 241.79,95.85 | 241.79,95.85 242.3,96.35 243.83,96.35 245.35,97.88 A06.N1 | 241.79,95.85 v241.54,96.1 | 254.87,116.93 258.05,116.93 A05.F1 | 254.87,116.93 253.1,116.93 A05.F2 | 254.87,116.93 254.87,116.8 252.72,114.64 252.72,111.72 A05.J2 252.08,110.2 251.95,110.2 249.92,108.17 A06.K1 248.52,107.4 247,105.88 245.48,105.88 243.32,103.72 v243.32,103.59 | v248.78,122.39 248.72,122.45 | A03.C2 283.32,126.45 288.15,126.45 A03.C1 289.04,127.6 289.04,128.36 | 289.04,128.36 289.04,132.42 A03.A1 | A02.F1 298.82,118.07 298.82,122.39 299.71,123.28 299.71,124.55 301.23,126.07 A02.C1 | 289.04,128.36 293.61,128.36 294.62,127.34 A02.C2 | 273.92,131.28 272.65,131.28 271.51,130.14 271,130.14 268.08,127.22 262.62,127.22 A05.C1 | 273.92,131.28 275.45,132.8 A04.A1
  Bottom 0.381: A04.F2 267.07,118.07 267.07,120.23 269.99,123.15 269.99,126.07 A04.C2 270.62,126.45 274.31,126.45 | 274.31,126.45 275.45,126.45 A04.C1 275.83,127.6 276.72,128.49 273.92,131.28 | A06.U2 243.57,82.77 243.57,82.89 245.6,84.92 A06.T1 | v250.3,92.93 v248.27,90.89 248.02,90.51 v245.22,87.72 | v250.94,94.58 250.94,96.35 252.08,97.5 A05.N2 253.1,98.64 255.64,98.64 262.24,105.24 262.24,107.02 A05.K1 262.62,107.53 265.67,110.58 265.92,110.58 A04.J2 267.45,111.34 268.97,112.86 270.24,112.86 272.65,115.28 272.65,116.55 A04.F1 273.42,118.07 274.31,118.96 274.31,126.45 | v224.9,122.9 224.9,123.41 226.43,124.93 227.95,124.93 229.47,126.45 A07.C2 230.87,127.22 231.63,127.98 v231.76,127.98 | 148.7,115.79 148.7,112.99 147.94,112.23 147.94,111.72 A13.J2 146.92,110.58 143.11,110.58 141.84,109.31 141.46,109.31 138.67,106.52 137.15,106.52 135.62,104.99 A14.L2 | 148.7,115.79 147.94,116.55 A13.F2 | 148.7,115.79 159.37,126.45 164.32,126.45 A12.C2 165.85,126.45 166.74,125.56 171.82,125.56 172.71,126.45 v173.09,126.45 | v183.37,130.26 182.87,130.26 181.34,128.74 180.07,128.74 178.55,127.22 A11.C2 | v197.72,122.52 198.74,123.53 198.74,124.04 200.01,125.31 200.77,125.31 201.92,126.45 202.42,126.45 A09.C2 | v211.19,120.87 213.09,122.77 213.09,124.29 214.11,125.31 215,125.31 216.14,126.45 216.77,126.45 A08.C2 | A13.C2 150.1,126.45 148.58,126.45 136.89,114.77 136.89,113.37 135.24,111.72 A14.J2 | 98.03,121.75 98.03,126.07 A17.C2 | 98.03,121.75 97.14,120.87 97.14,119.6 95.62,118.07 A17.F2 | A18.U2 86.47,82.77 87.74,82.77 93.33,88.35 93.33,89.62 94.85,91.15 A17.R2 96,92.29 100.31,92.29 104.38,96.35 107.3,96.35 108.82,97.88 A16.N2
  Bottom 0.381: A16.J2 109.2,111.72 109.2,116.55 A16.F2 109.84,118.07 111.49,119.72 111.49,121.12 112,121.63 | 112.38,125.56 112.38,122.01 112,121.63 | 112.38,125.56 112.38,126.07 A16.C2 | A15.C2 124.7,126.45 120.51,126.45 119.62,125.56 112.38,125.56 | 98.03,121.75 111.87,121.75 112,121.63 | v238.87,125.56 239.76,126.45 242.17,126.45 A06.C2 | v246.62,37.81 247.25,37.81 248.65,39.2 250.18,39.2 251.7,40.73 B05.J2 | v250.18,42.89 249.41,42.13 248.02,43.52 248.02,44.92 250.18,47.08 251.7,47.08 B05.F2 | 259.45,59.02 259.95,59.52 259.95,60.92 261.61,62.57 B05.A1 | 259.45,59.02 258.94,58.51 258.94,58.13 257.16,56.35 v257.16,55.84 256.78,55.59 251.7,50.51 v251.7,50.38 | 259.45,59.02 v259.7,58.76 | 274.56,54.95 275.83,56.22 B04.C1 276.59,57.75 276.85,58 276.85,60.54 277.35,61.05 v277.35,61.68 | 274.56,54.95 274.31,54.7 274.31,53.43 273.16,52.29 272.65,52.29 271.13,50.76 271.13,50.25 268.72,47.84 267.45,47.84 B04.F2 266.3,46.7 v263.76,44.16 | B04.C2 270.62,56.6 272.4,54.83 272.65,55.08 274.43,55.08 274.56,54.95 | B05.U2 256.27,12.92 256.27,13.04 258.3,15.08 B05.T1 | B06.T1 246.75,16.09 248.27,16.09 250.43,18.25 250.43,19.65 252.08,21.3 B05.R2 253.1,22.44 254.11,22.44 254.75,23.08 255.26,23.08 256.78,24.6 256.78,26 258.43,27.65 B05.N1 259.45,28.79 261.1,28.79 266.3,34 B04.L2 | B03.A1 288.53,62.57 287,61.05 287,59.78 284.59,57.37 283.32,57.37 B03.C2 282.18,56.22 282.18,54.95 276.59,49.37 275.83,49.37 274.05,47.59 274.05,47.46 | 274.05,47.46 276.46,47.46 277.23,48.22 278.12,48.22 | 278.12,48.22 279,48.22 B03.F2 | 274.05,47.46 B04.F1 272.65,46.7 272.65,45.43 270.24,43.02 268.97,43.02 267.45,41.49 B04.J2 265.92,40.73 265.03,40.73 262.62,38.32 B05.K1
  Bottom 0.381: v253.86,27.01 254.62,27.01 v255.64,28.03 | v287,57.75 287,57.24 278.12,48.35 278.12,48.22 | B01.C1 314.69,57.75 314.69,59.91 315.2,60.41 315.2,62.06 314.69,62.57 B01.A1 | 297.17,55.59 298.94,57.37 300.85,57.37 B02.C1 301.23,57.75 301.23,62.57 B02.A1 | 297.17,55.59 296.91,55.33 296.4,55.33 295.9,54.83 295.9,54.7 290.43,49.24 291.58,48.09 B02.F2 | 297.17,55.59 v297.04,55.72 | v311.39,58.51 309.87,58.51 308.72,57.37 B01.C2 | B02.U2 296.02,12.92 298.05,14.95 B02.T1 | B02.K1 302.37,38.32 304.4,40.35 B01.J2 304.4,41.87 304.4,46.7 B01.F2 305.55,47.84 306.69,48.98 v307.96,48.98 | B02.R1 298.82,22.82 298.82,24.09 301.23,26.51 301.61,26.51 303.01,27.9 303.9,27.9 304.02,28.03 B01.N2 | B01.R2 305.17,22.82 306.69,24.35 306.69,25.62 309.1,28.03 310.37,28.03 B01.N1 311.52,29.17 313.04,30.7 313.04,31.97 313.93,32.86 313.93,37.17 B01.K1 | B04.R1 273.8,22.44 275.07,22.44 277.48,24.85 277.48,26.12 279,27.65 B03.N2 | B04.U2 270.62,12.92 272.65,14.95 B04.T1 | v264.4,25.36 266.3,27.27 266.3,27.65 B04.N2 | B04.R2 267.45,22.44 268.97,23.96 270.24,23.96 272.65,26.38 272.65,27.65 B04.N1 273.42,29.17 273.42,30.44 275.83,32.86 277.1,32.86 278.62,34.38 B03.L2 | B04.K1 276.97,38.32 279,40.35 B03.J2 279.77,41.87 279.77,43.14 282.18,45.55 283.45,45.55 284.97,47.08 B03.F1 | B02.J2 291.7,40.35 289.67,38.32 B03.K1 | B03.U2 283.32,12.92 285.35,14.95 B03.T1 286.5,16.09 287.77,16.09 290.18,18.5 290.18,19.77 291.7,21.3 B02.R2 291.7,22.82 291.7,27.65 B02.N2 292.85,28.03 297.67,28.03 B02.N1 | B07.L2 226.43,34.25 225.28,33.11 223,33.11 222.62,32.73 220.84,32.73 218.81,34.76 223.25,39.2 224.78,39.2 226.3,40.73 B07.J2
  Bottom 0.381: B07.U2 230.87,12.92 230.87,13.04 232.9,15.08 B07.T1 | 231.7,23.27 234.55,26.12 234.55,27.01 233.79,27.78 B07.N1 v230.62,28.41 230.87,28.79 232.08,30 | 231.7,23.27 230.11,21.68 227.7,21.68 B07.R2 226.68,21.3 225.41,20.03 v225.41,19.01 | 231.7,23.27 v231.76,23.2 | v238.11,35.9 237.98,35.9 232.08,30 | 232.08,30 v232.14,29.93 | v183.12,58.26 181.47,56.6 v180.71,56.6 180.45,56.22 180.45,56.1 v172.71,48.35 | v195.31,60.41 195.31,60.16 194.04,58.89 192.77,58.89 191.25,57.37 B10.C2 | 229.6,53.56 228.71,54.45 228.71,55.21 229.73,56.22 229.86,56.22 B07.C2 | 234.62,58.57 235.82,59.78 235.82,62.19 236.21,62.57 B07.A1 | 229.6,53.56 234.62,58.57 | 234.62,58.57 v234.55,58.64 | v241.29,54.45 242.56,55.72 242.56,56.22 B06.C2 243.57,57.37 245.1,58.89 246.62,58.89 251.06,63.34 251.06,63.84 251.57,64.35 254.37,64.35 255.13,65.11 256.91,65.11 257.16,65.37 v259.45,65.37 | v226.81,50.63 229.47,53.3 229.47,53.43 229.6,53.56 | v211.82,64.1 211.82,63.97 205.22,57.37 203.95,57.37 B09.C2 | v237.98,40.6 236.84,39.46 236.84,38.7 B07.K1 | B21.V2 43.55,9.74 43.55,9.87 45.58,11.9 B21.U2 | B23.U2 21.32,12.92 25.51,12.92 26.4,13.81 27.93,13.81 29.45,15.33 B22.T2 | B21.T2 42.15,15.33 37.96,15.33 37.07,14.44 35.55,14.44 34.02,12.92 B22.U2 | B16.V2 110.22,9.74 110.22,9.87 112.25,11.9 B16.U2 | B17.V2 96,9.74 98.03,11.77 B17.U2 99.17,12.92 100.7,14.44 101.97,14.44 102.86,15.33 108.82,15.33 B16.T2 109.84,16.47 109.84,19.52 144.13,53.81 v144.38,54.19 146.16,54.19 147.05,55.08 | B18.V2 83.3,9.74 85.33,11.77 B18.U2 86.47,12.92 88,14.44 89.27,14.44 90.16,15.33 94.47,15.33 B17.T2 | B20.V2 57.9,9.74 59.93,11.77 B20.U2
  Bottom 0.381: B18.T2 81.77,15.33 77.45,15.33 76.57,14.44 75.3,14.44 73.77,12.92 B19.U2 | v120.76,52.54 122.79,52.54 123.43,53.18 123.43,54.57 125.08,56.22 B15.C2 126.1,57.37 128.89,57.37 v133.08,61.56 | 147.05,55.08 148.58,55.08 150.1,56.6 B13.C2 | v159.75,63.34 157.47,65.62 150.86,59.02 149.34,59.02 147.18,56.86 147.18,55.21 147.05,55.08 | A15.U2 126.1,82.77 127.62,82.77 132.95,88.1 132.95,89.5 134.61,91.15 A14.R2 135.62,92.29 137.15,93.81 138.67,93.81 147.31,102.45 147.31,103.85 A13.L2 | 107.36,89.56 109.08,91.27 A16.R2 | 107.36,89.56 100.57,82.77 99.17,82.77 A17.U2 | 112.38,84.54 112.38,83.15 A16.U2 | 112.38,84.54 107.36,89.56 | 112.38,84.54 112.51,84.67 113.14,84.67 118.48,90 120,90 121.52,91.53 A15.R2
I_3CYCLE  (via drill 0.61)
  Top 0.152: v132.95,4.41 132.19,5.17 129.53,5.17 128.26,6.44 126.86,6.44 125.08,8.22 115.43,8.22 105.9,17.74 98.03,17.74 83.68,32.09 83.68,35.14 71.74,47.08 70.6,47.08 B19.F2 | v171.69,42.51 174.23,39.97 177.28,39.97 207.5,9.74 207.5,8.85 v212.46,3.9 | v241.41,122.64 242.43,121.63 243.32,121.63 255.26,109.69 255.26,108.55 A05.K2 | v240.27,121.5 237.09,121.5 v222.49,136.11 | v201.79,116.42 201.79,114.01 v211.82,103.97 | v164.2,46.19 164.83,46.19 169.4,41.62 169.4,40.22 v169.53,40.09
  Bottom 0.152: v132.95,4.41 132.95,4.66 134.48,6.18 135.37,6.18 169.4,40.22 | v171.69,42.51 169.4,40.22 | v212.46,3.9 217.92,3.9 228.46,14.44 228.71,14.44 235.7,21.43 235.7,21.93 238.24,24.47 238.24,25.36 244.46,31.59 245.1,31.59 247.51,34 248.52,34 248.91,34.38 251.06,34.38 252.33,33.11 253.48,34.25 253.48,35.4 255.26,37.17 B05.K2 | v240.27,121.5 v241.41,122.64 | v222.49,136.11 221.98,136.11 214.74,128.87 214.36,128.87 201.92,116.42 v201.79,116.42 | v211.82,103.97 211.82,101.82 211.57,101.56 211.57,99.66 195.82,83.91 195.31,83.91 174.23,62.83 174.23,61.3 167.12,54.19 167.12,49.11 v164.2,46.19 | 169.4,40.22 v169.53,40.09
I_AC00  (via drill 0.61)
  Top 0.152: v119.49,52.41 119.24,52.67 115.43,52.67 114.67,53.43 110.22,53.43 B16.D2 | v161.66,90.26 162.04,90.26 174.23,78.07 v177.02,78.07 | v233.28,134.71 233.41,134.71 239.25,128.87 242.3,128.87 v242.56,128.61 | v257.41,138.9 275.32,138.9 282.18,132.04 283.32,132.04 284.97,130.39 A03.B1 286.5,129.63 288.15,127.98 289.29,127.98 305.93,111.34 v305.93,109.44 | v278.37,70.07 278.75,69.68 278.75,68.54 281.42,65.88 281.42,62.95 283.83,60.54 284.97,60.54 B03.B1
  Bottom 0.152: v119.49,52.41 119.49,52.67 124.95,58.13 128.51,58.13 132.7,62.32 133.72,62.32 v161.66,90.26 | v177.02,78.07 177.28,78.07 215.76,116.55 215.76,117.18 v233.28,134.71 | v242.56,128.61 243.06,128.61 248.78,134.33 252.84,134.33 v257.41,138.9 | v278.37,70.07 279,70.07 283.32,74.38 283.32,77.69 284.59,78.96 284.59,80.61 290.81,86.83 290.81,87.34 295.39,91.91 295.9,91.91 300.47,96.48 300.47,98.77 302.75,101.05 302.75,106.26 v305.93,109.44
I_AC01  (via drill 0.61)
  Top 0.152: v97.14,61.68 109.2,49.62 109.2,48.22 B16.F2 | v163.31,134.58 173.59,134.58 198.36,109.82 198.36,109.18 208.77,98.77 209.54,98.77 222.62,85.69 222.62,85.18 225.16,82.64 225.16,82.51 225.54,82.13 226.17,82.13 230.11,78.19 | 230.11,78.19 248.14,60.16 248.14,59.65 259.19,48.6 260.46,48.6 v265.92,43.14 | v279.26,57.24 280.78,57.24 282.18,55.84 283.32,55.84 284.97,54.19 B03.D1 | v264.91,104.86 262.11,104.86 v261.35,105.63 | 230.11,78.19 v230.11,77.56
  Bottom 0.152: v97.14,61.68 97.14,64.22 101.97,69.05 101.97,69.3 102.22,69.56 102.22,69.94 102.35,70.07 102.35,70.32 102.47,70.45 102.47,73.75 109.08,80.35 112.25,80.35 123.3,91.4 123.3,95.97 132.32,104.99 132.7,104.99 134.35,106.64 134.86,106.64 150.23,122.01 150.73,122.01 v163.31,134.58 | v265.92,43.14 273.8,51.02 273.8,51.78 v279.26,57.24 | v264.91,104.86 283.32,123.28 284.97,123.28 A03.D1 | v261.35,105.63 256.02,100.29 252.84,100.29 v230.11,77.56
I_AC02  (via drill 0.61)
  Top 0.152: v155.69,4.53 142.48,17.74 137.65,17.74 134.86,20.54 134.35,20.54 129.4,25.49 128.38,25.49 117.08,36.79 v116.32,36.79 112.25,36.79 109.84,39.2 109.84,40.35 B16.J2 | v196.45,33.49 199.63,33.49 201.53,31.59 201.53,31.2 211.31,21.43 211.69,21.43 218.43,14.69 218.43,14.06 224.01,8.47 225.16,8.47 227.19,6.44 v230.62,6.44 | v266.3,32.22 266.94,32.22 v268.72,30.44 | v273.04,133.44 285.1,121.37 287.64,121.37 288.15,120.87 A03.E1 | v244.08,115.91 242.68,115.91 240.14,118.45 236.59,118.45 v236.33,118.71 | v233.03,115.4 232.4,115.4 v226.17,121.63 | v218.04,117.06 217.28,117.06 v211.69,122.64 | v207.88,119.72 207,119.72 204.33,122.39 203.57,122.39 v194.8,131.15 | v146.04,79.21 146.04,71.34 v146.16,71.21
  Bottom 0.152: v155.69,4.53 167.5,4.53 v196.45,33.49 | v230.62,6.44 235.19,6.44 239.25,10.5 244.59,10.5 v266.3,32.22 | v268.72,30.44 270.75,30.44 280.91,40.6 280.91,41.11 288.66,48.86 288.66,49.87 B03.E1 | v273.04,133.44 270.37,130.77 268.97,130.77 267.07,128.87 261.48,128.87 259.06,126.45 257.29,126.45 255.76,124.93 255.26,124.93 246.49,116.17 244.33,116.17 v244.08,115.91 | v233.03,115.4 v236.33,118.71 | v226.17,121.63 222.62,121.63 v218.04,117.06 | v211.69,122.64 210.17,122.64 208.39,120.87 208.39,120.23 v207.88,119.72 | v194.8,131.15 193.28,131.15 179.82,117.69 179.82,114.64 162.29,97.12 162.04,97.12 153.27,88.35 153.27,86.45 v146.04,79.21 | v146.16,71.21 146.16,66.64 v116.32,36.79
I_AC03  (via drill 0.61)
  Top 0.152: v122.67,45.43 128.51,45.43 131.18,42.76 131.68,42.76 156.7,17.74 158.35,17.74 161.53,14.57 165.59,14.57 167.37,12.79 168.51,12.79 v173.09,8.22 | v190.61,16.98 195.31,16.98 v201.28,11.01 | v232.01,38.19 232.65,38.19 239.25,31.59 239.25,30.95 v254.24,15.96 | v262.24,23.2 263.51,23.2 v264.65,22.06 | v304.79,89.75 291.07,103.47 291.07,104.1 287.39,107.78 288.53,108.93 289.29,108.93 290.43,107.78 293.23,110.58 293.23,111.34 290.81,113.75 289.67,113.75 A03.H1 | v303.39,88.35 303.51,88.35 307.2,84.67 307.2,84.54 308.21,83.53 308.34,83.53 v315.96,75.91 | v315.07,68.92 315.07,64.6 v317.87,61.81 | v300.98,33.24 300.98,33.74 298.82,35.9 295.77,35.9 290.94,40.73 290.94,42.25 B03.H1
  Bottom 0.152: v122.67,45.43 116.32,39.08 112.25,39.08 109.84,36.66 109.84,35.52 B16.L2 | v173.09,8.22 181.85,8.22 v190.61,16.98 | v201.28,11.01 204.84,11.01 v232.01,38.19 | v254.24,15.96 255,15.96 v262.24,23.2 | v264.65,22.06 270.11,27.52 270.11,28.28 280.4,38.57 281.67,38.57 285.35,42.25 286.5,42.25 288.15,43.9 B03.H1 | v303.39,88.35 v304.79,89.75 | v315.96,75.91 315.96,69.81 v315.07,68.92 | v317.87,61.81 317.87,52.03 317.1,51.27 317.1,49.11 311.13,43.14 311.13,42.63 309.99,41.49 309.99,37.94 307.71,35.65 307.2,35.65 305.17,33.62 301.36,33.62 v300.98,33.24
I_AC04  (via drill 0.61)
  Top 0.152: v127.62,39.2 133.34,39.2 v152,20.54 | v192.14,61.3 200.9,61.3 v209.54,52.67 | v211.69,54.45 212.08,54.45 214.23,52.29 214.36,52.29 216.39,50.25 216.39,50.13 220.2,46.32 221.85,46.32 222.24,45.94 223.76,45.94 231.25,38.44 231.25,37.81 231.63,37.43 232.9,37.43 238.87,31.46 238.87,30.82 253.48,16.22 253.48,14.95 253.86,14.57 255.13,14.57 264.02,5.68 264.02,5.55 264.4,5.17 v266.3,5.17 | v281.93,21.93 v274.81,29.05 | v272.53,121.75 282.94,111.34 284.97,111.34 A03.J1 | v250.81,100.93 250.81,101.43 249.67,102.58 246.49,102.58 241.79,107.28 241.79,110.45 236.97,115.28 236.59,115.28 235.7,116.17 235.7,117.44 229.98,123.15 229.98,124.68 218.81,135.85 215.76,135.85 v215.25,136.36 | v197.34,130.01 197.34,129.76 v198.36,128.74 | v173.47,99.4 173.47,95.85 v198.36,70.95
  Bottom 0.152: v127.62,39.2 127.49,39.08 124.95,39.08 122.16,36.28 121.65,36.28 114.16,28.79 110.22,28.79 B16.N2 | v152,20.54 154.04,20.54 158.23,24.73 158.23,26.25 180.58,48.6 181.09,48.6 182.23,49.75 182.23,51.4 v192.14,61.3 192.26,61.68 198.36,67.78 v198.36,70.95 | v209.54,52.67 209.92,52.67 v211.69,54.45 | v266.3,5.17 281.29,20.16 281.29,21.3 v281.93,21.93 | v274.81,29.05 275.19,29.05 283.7,37.55 283.7,38.7 285.35,40.35 B03.J1 | v272.53,121.75 272.53,121.63 267.07,116.17 263.51,116.17 263.26,115.91 261.48,115.91 252.59,107.02 252.59,106.39 251.32,105.12 251.32,101.43 v250.81,100.93 | v215.25,136.36 203.69,136.36 v197.34,130.01 | v198.36,128.74 198.36,126.83 178.17,106.64 177.66,106.64 176.9,105.88 176.9,102.83 v173.47,99.4
I_AC05  (via drill 0.61)
  Top 0.152: v124.32,35.9 129.27,35.9 136.51,28.66 | 136.51,28.66 144.26,20.92 145.02,20.92 150.23,15.71 151.88,15.71 156.58,11.01 158.23,11.01 161.4,7.84 171.31,7.84 172.45,6.69 178.29,6.69 v183.25,1.74 | v251.06,12.41 251.95,12.41 v253.48,10.88 | v280.91,37.81 281.16,37.81 282.18,36.79 283.32,36.79 284.97,35.14 B03.L1 | v285.99,107.78 285.35,107.78 271.76,121.37 271.76,122.01 269.48,124.29 269.23,124.29 v260.34,133.19 | v233.03,122.01 233.03,122.39 231.12,124.29 230.87,124.29 v217.03,138.14 | v205.98,138.14 204.96,138.14 v204.33,138.77 | v183.25,117.56 183.25,116.55 v202.17,97.62 | 136.51,28.66 v136.51,28.03
  Bottom 0.152: v124.32,35.9 123.3,34.89 123.3,34.25 111.49,22.44 110.22,22.44 B16.R2 | v183.25,1.74 184.26,0.72 235.06,0.72 236.33,1.99 239.51,1.99 244.08,6.57 245.35,6.57 251.06,12.28 v251.06,12.41 | v253.48,10.88 255.51,10.88 263,18.38 263,19.27 265.42,21.68 265.42,22.31 270.5,27.39 270.5,28.16 275.83,33.49 276.59,33.49 v280.91,37.81 | v285.99,107.78 285.99,105.37 A03.L1 | v260.34,133.19 260.34,134.46 263.26,137.38 263.26,138.14 261.22,140.17 251.45,140.17 233.79,122.52 233.54,122.52 v233.03,122.01 | v205.98,138.14 v217.03,138.14 | v204.33,138.77 204.33,138.65 v183.25,117.56 | v202.17,97.62 202.17,95.59 179.82,73.24 179.82,73.11 171.18,64.48 171.05,64.48 160.77,54.19 160.77,52.29 v136.51,28.03
I_AC06  (via drill 0.61)
  Top 0.152: v287.77,33.11 288.53,32.35 B03.M1 289.29,30.82 289.42,30.7 v289.42,29.43 | v317.87,68.29 317.87,79.08 318.25,79.46 318.25,118.07 314.69,121.63 309.48,121.63 v308.47,122.64 | v106.54,44.67 97.78,53.43 96,53.43 B17.D2 | v130.16,63.21 130.29,63.21 137.65,55.84 140.83,55.84 158.23,38.44 158.23,35.4 158.61,35.01 158.61,34.63 160.39,32.86 161.15,32.86 171.56,22.44 172.71,22.44 174.23,20.92 178.04,20.92 193.79,5.17 204.33,5.17 v207.5,1.99 | v239.25,2.88 242.17,2.88 v242.43,2.63 | v253.1,13.3 253.1,12.92 258.18,7.84 260.08,7.84 v264.53,3.39
  Bottom 0.152: v287.77,33.11 288.28,33.11 295.13,39.97 295.13,40.35 300.34,45.55 300.34,46.83 306.18,52.67 306.69,52.67 312.15,58.13 312.15,59.65 312.28,59.78 312.28,63.34 313.8,64.86 314.44,64.86 v317.87,68.29 | v308.47,122.64 308.09,122.64 289.55,104.1 289.55,102.45 289.29,102.2 A03.M1 | v106.54,44.67 108.82,44.67 114.79,50.63 116.57,50.63 119.11,53.18 119.49,53.18 128,61.68 128.64,61.68 v130.16,63.21 | v207.5,1.99 235.82,1.99 236.21,2.38 238.75,2.38 v239.25,2.88 | v253.1,13.3 v242.43,2.63 | v264.53,3.39 265.67,3.39 267.07,4.79 267.07,5.42 281.67,20.03 281.67,20.54 282.69,21.55 282.69,22.7 v289.42,29.43
I_AC07  (via drill 0.61)
  Top 0.152: v301.61,41.62 301.61,42.63 300.59,43.65 299.96,43.65 286.24,57.37 286.24,57.62 281.04,62.83 281.04,64.1 v280.66,64.48 | v286.75,70.57 v282.56,74.77 | v290.05,87.21 290.05,91.27 v287.77,93.56 | v119.11,27.27 105.65,40.73 103.11,40.73 102.73,41.11 102.73,41.49 97.14,47.08 96,47.08 B17.F2 | v126.98,29.55 131.18,29.55 144.38,16.35 144.89,16.35 153.4,7.84 154.93,7.84 157.08,5.68 157.97,5.68 160.51,8.22 161.28,7.46 170.55,7.46 v171.44,6.57 | v199.25,20.03 199.38,20.03 206.23,13.17 207.38,13.17 209.15,11.39 214.23,11.39 218.55,7.07 219.06,7.07 220.84,5.3 221.98,5.3 222.74,4.53 v231.38,4.53 | v257.16,19.27 259.57,19.27 262.75,16.09 264.78,16.09 269.48,11.39 273.04,11.39 v274.69,9.74
  Bottom 0.152: v301.61,41.62 290.18,30.19 290.18,29.05 289.29,28.16 289.29,26 B03.P1 288.53,24.47 286.88,22.82 286.88,21.68 274.94,9.74 v274.69,9.74 | v280.66,64.48 v286.75,70.57 | v282.56,74.77 282.56,77.43 284.21,79.08 284.21,81.37 v290.05,87.21 | v287.77,93.56 288.53,94.32 A03.P1 | v119.11,27.27 124.7,27.27 v126.98,29.55 | v171.44,6.57 180.71,6.57 188.33,14.19 190.61,14.19 196.45,20.03 v199.25,20.03 | v231.38,4.53 232.01,4.53 233.16,5.68 236.21,5.68 238.75,8.22 243.32,8.22 251.95,16.85 255.13,16.85 256.65,18.38 256.65,18.76 v257.16,19.27
I_AC08  (via drill 0.61)
  Top 0.152: v289.42,23.08 288.78,23.08 279.89,31.97 279.89,32.73 v273.54,39.08 | v284.97,51.65 v287.26,51.65 | v298.05,63.84 298.05,64.35 288.91,73.49 288.91,74 v283.45,79.46 | v99.17,42 104.38,36.79 105.39,36.79 134.35,7.84 138.29,7.84 v138.8,7.33 | v180.83,42.76 188.45,35.14 188.45,32.09 v197.22,23.33 | v213.47,32.6 214.87,32.6 226.55,20.92 230.62,20.92 v241.79,9.74
  Bottom 0.152: v289.42,23.08 289.29,22.95 289.29,19.65 B03.S1 | v284.97,51.65 284.97,51.52 276.59,43.14 276.46,43.14 274.81,41.49 274.81,41.36 273.54,40.09 v273.54,39.08 273.16,38.95 267.07,32.86 267.07,31.84 266.69,31.46 266.56,31.46 252.33,17.23 251.83,17.23 244.33,9.74 v241.79,9.74 | v287.26,51.65 287.26,52.29 290.18,55.21 290.18,55.97 v298.05,63.84 | v283.45,79.46 283.45,81.75 286.88,85.18 286.88,86.32 288.53,87.97 A03.S1 | v99.17,42 98.66,41.49 96,41.49 B17.J2 | v138.8,7.33 147.18,7.33 158.23,18.38 158.23,20.16 v180.83,42.76 | v197.22,23.33 204.2,23.33 v213.47,32.6
I_AC09  (via drill 0.61)
  Top 0.152: v115.17,49.87 118.22,49.87 118.6,49.49 131.3,49.49 v145.78,35.01 | v189.6,70.32 190.87,70.32 191.88,69.3 195.69,69.3 v212.84,52.16 | v229.86,69.81 230.74,69.81 v234.81,65.75 | v241.03,68.92 241.54,68.92 252.08,58.38 252.97,58.38 254.37,56.98 254.37,56.6 258.3,52.67 258.81,52.67 v259.32,52.16 | v271.64,63.08 277.35,57.37 277.35,57.24 | 277.35,57.24 277.35,56.22 279,54.57 B03.D2 | v288.15,130.77 288.15,130.14 314.31,103.97 314.31,102.96 315.45,101.82 315.45,99.78 316.85,98.39 316.85,94.58 314.44,92.16 v309.87,96.74 | 277.35,57.24 v277.99,57.24
  Bottom 0.152: v115.17,49.87 100.44,35.14 96,35.14 B17.L2 | v145.78,35.01 146.29,35.01 147.18,35.9 151.88,35.9 157.08,41.11 159.37,41.11 159.88,41.62 160.89,41.62 v189.6,70.32 | v212.84,52.16 213.47,52.16 213.6,52.29 214.36,52.29 221.73,59.65 221.73,62.83 223.38,64.48 224.52,64.48 v229.86,69.81 | v234.81,65.75 237.86,65.75 v241.03,68.92 | v259.32,52.16 260.72,52.16 v271.64,63.08 | v288.15,130.77 285.35,127.98 282.18,127.98 279.77,125.56 279.77,124.42 A03.D2 | v309.87,96.74 309.87,92.16 297.29,79.59 297.29,77.18 294.37,74.26 294.37,73.62 v277.99,57.24
I_AC10  (via drill 0.61)
  Top 0.152: v105.39,20.92 98.28,28.03 96,28.03 B17.N2 | v209.28,118.2 211.69,118.2 v212.71,117.18 | v229.22,131.79 v231.51,131.79 | v236.97,137.5 242.43,132.04 244.84,132.04 v245.1,131.79 | v253.1,135.72 261.73,135.72 v265.92,131.53 | v269.99,131.53 279,122.52 280.15,122.52 281.8,120.87 A03.E2 | v291.7,49.24 291.7,49.37 288.4,52.67 285.35,52.67 284.21,53.81 282.94,52.54 282.94,51.4 B03.E2 | v296.78,54.45 296.28,54.45 287.77,62.95 287.77,65.24 v279.89,73.11 | v286.75,88.1 286.75,89.37 281.42,94.7 280.66,94.7 v269.48,105.88
  Bottom 0.152: v105.39,20.92 110.47,20.92 130.92,41.36 130.92,41.87 144,54.95 144.64,54.95 149.21,59.52 150.73,59.52 167.75,76.54 169.28,76.54 190.61,97.88 190.61,100.04 192.26,101.69 192.26,101.82 192.64,102.2 193.28,102.2 v209.28,118.2 | v212.71,117.18 212.71,117.82 216.9,122.01 217.41,122.01 226.55,131.15 228.59,131.15 v229.22,131.79 | v231.51,131.79 234.05,134.33 234.05,134.58 v236.97,137.5 | v245.1,131.79 245.73,131.79 248.65,134.71 252.08,134.71 v253.1,135.72 | v265.92,131.53 v269.99,131.53 | v291.7,49.24 291.7,49.37 v296.78,54.45 | v279.89,73.11 279.89,76.54 280.53,77.18 280.53,81.88 v286.75,88.1 | v269.48,105.88 280.53,116.93 280.53,118.07 282.18,119.72 A03.E2
I_AC11  (via drill 0.61)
